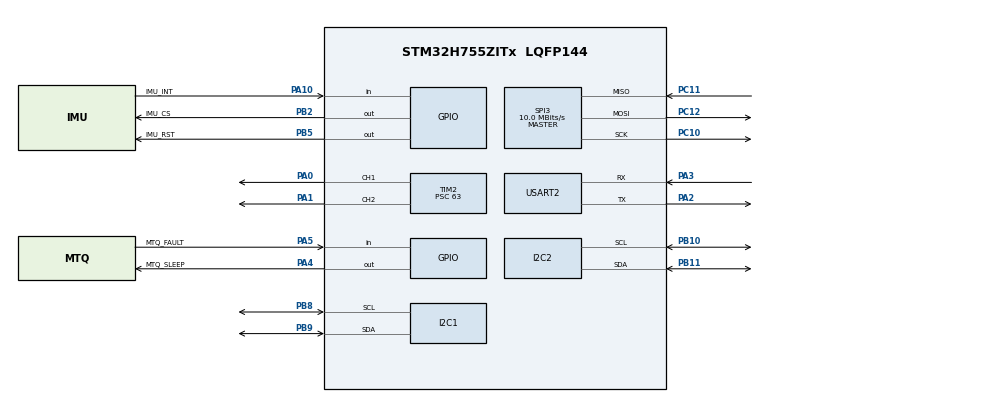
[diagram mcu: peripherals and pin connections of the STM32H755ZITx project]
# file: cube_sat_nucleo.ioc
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CORTEX_M7.default_mode_Activation=1
CortexM4.IPs=BDMA,CORTEX_M4\:I,DMA,FATFS_M4\:I,FREERTOS_M4\:I,GPIO,IWDG2\:I,MDMA,NVIC2\:I,OPENAMP_M4\:I,PDM2PCM_M4\:I,PWR,RCC,RESMGR_UTILITY,SYS_M4\:I,USB_DEVICE_M4\:I,USB_HOST_M4\:I,VREFBUF,WWDG2\:I
CortexM7.IPs=BDMA\:I,CORTEX_M7\:I,DMA\:I,FATFS_M7\:I,FREERTOS_M7\:I,GPIO\:I,IWDG1\:I,MDMA\:I,NVIC1\:I,OPENAMP_M7\:I,PDM2PCM_M7\:I,PWR\:I,RCC\:I,RESMGR_UTILITY\:I,SYS\:I,USB_DEVICE_M7\:I,USB_HOST_M7\:I,VREFBUF\:I,WWDG1\:I,MEMORYMAP\:I,TIM2\:I,TIM6\:I,SPI3\:I,I2C1\:I,USART2\:I,I2C2\:I
Dma.Request0=USART2_TX
Dma.Request1=SPI3_RX
Dma.Request2=SPI3_TX
Dma.SPI3_RX.1.Direction=DMA_PERIPH_TO_MEMORY
Dma.SPI3_RX.1.EventEnable=DISABLE
Dma.SPI3_RX.1.FIFOMode=DMA_FIFOMODE_DISABLE
Dma.SPI3_RX.1.Instance=DMA2_Stream1
Dma.SPI3_RX.1.MemDataAlignment=DMA_MDATAALIGN_BYTE
Dma.SPI3_RX.1.MemInc=DMA_MINC_ENABLE
Dma.SPI3_RX.1.Mode=DMA_NORMAL
Dma.SPI3_RX.1.PeriphDataAlignment=DMA_PDATAALIGN_BYTE
Dma.SPI3_RX.1.PeriphInc=DMA_PINC_DISABLE
Dma.SPI3_RX.1.Polarity=HAL_DMAMUX_REQ_GEN_RISING
Dma.SPI3_RX.1.Priority=DMA_PRIORITY_LOW
Dma.SPI3_RX.1.RequestNumber=1
Dma.SPI3_RX.1.SignalID=NONE
Dma.SPI3_RX.1.SyncEnable=DISABLE
Dma.SPI3_RX.1.SyncPolarity=HAL_DMAMUX_SYNC_NO_EVENT
Dma.SPI3_RX.1.SyncRequestNumber=1
Dma.SPI3_RX.1.SyncSignalID=NONE
Dma.SPI3_TX.2.Direction=DMA_MEMORY_TO_PERIPH
Dma.SPI3_TX.2.EventEnable=DISABLE
Dma.SPI3_TX.2.FIFOMode=DMA_FIFOMODE_DISABLE
Dma.SPI3_TX.2.Instance=DMA2_Stream2
Dma.SPI3_TX.2.MemDataAlignment=DMA_MDATAALIGN_BYTE
Dma.SPI3_TX.2.MemInc=DMA_MINC_ENABLE
Dma.SPI3_TX.2.Mode=DMA_NORMAL
Dma.SPI3_TX.2.PeriphDataAlignment=DMA_PDATAALIGN_BYTE
Dma.SPI3_TX.2.PeriphInc=DMA_PINC_DISABLE
Dma.SPI3_TX.2.Polarity=HAL_DMAMUX_REQ_GEN_RISING
Dma.SPI3_TX.2.Priority=DMA_PRIORITY_LOW
Dma.SPI3_TX.2.RequestNumber=1
Dma.SPI3_TX.2.SignalID=NONE
Dma.SPI3_TX.2.SyncEnable=DISABLE
Dma.SPI3_TX.2.SyncPolarity=HAL_DMAMUX_SYNC_NO_EVENT
Dma.SPI3_TX.2.SyncRequestNumber=1
Dma.SPI3_TX.2.SyncSignalID=NONE
Dma.USART2_TX.0.Direction=DMA_MEMORY_TO_PERIPH
Dma.USART2_TX.0.EventEnable=DISABLE
Dma.USART2_TX.0.FIFOMode=DMA_FIFOMODE_DISABLE
Dma.USART2_TX.0.Instance=DMA1_Stream7
Dma.USART2_TX.0.MemDataAlignment=DMA_MDATAALIGN_BYTE
Dma.USART2_TX.0.MemInc=DMA_MINC_ENABLE
Dma.USART2_TX.0.Mode=DMA_NORMAL
Dma.USART2_TX.0.PeriphDataAlignment=DMA_PDATAALIGN_BYTE
Dma.USART2_TX.0.PeriphInc=DMA_PINC_DISABLE
Dma.USART2_TX.0.Polarity=HAL_DMAMUX_REQ_GEN_RISING
Dma.USART2_TX.0.Priority=DMA_PRIORITY_LOW
Dma.USART2_TX.0.RequestNumber=1
Dma.USART2_TX.0.SignalID=NONE
Dma.USART2_TX.0.SyncEnable=DISABLE
Dma.USART2_TX.0.SyncPolarity=HAL_DMAMUX_SYNC_NO_EVENT
Dma.USART2_TX.0.SyncRequestNumber=1
Dma.USART2_TX.0.SyncSignalID=NONE
I2C1.Timing=0x00707CBB
I2C2.Timing=0x00707CBB
Mcu.Family=STM32H7
Mcu.Name=STM32H755ZITx
Mcu.Package=LQFP144
NVIC1.DMA1_Stream7_IRQn=true\:0\:0\:false\:false\:true\:false\:true\:true
NVIC1.DMA2_Stream1_IRQn=true\:0\:0\:false\:false\:true\:false\:true\:true
NVIC1.DMA2_Stream2_IRQn=true\:0\:0\:false\:false\:true\:false\:true\:true
NVIC1.PriorityGroup=NVIC_PRIORITYGROUP_4
NVIC1.SPI3_IRQn=true\:0\:0\:false\:false\:true\:true\:true\:true
NVIC1.TIM6_DAC_IRQn=true\:5\:0\:false\:false\:true\:true\:true\:true
NVIC2.PriorityGroup=NVIC_PRIORITYGROUP_4
PA0.PinAttribute=CortexM7
PA0.Signal=S_TIM2_CH1_ETR
PA1.PinAttribute=CortexM7
PA1.Signal=S_TIM2_CH2
PA10.GPIO_Label=IMU_INT
PA10.GPIO_PuPd=GPIO_PULLUP
PA10.PinAttribute=Free
PA10.Signal=GPIO_Input
PA2.GPIO_Speed=GPIO_SPEED_FREQ_VERY_HIGH
PA2.Mode=Asynchronous
PA2.PinAttribute=CortexM7
PA2.Signal=USART2_TX
PA3.GPIO_Speed=GPIO_SPEED_FREQ_VERY_HIGH
PA3.Mode=Asynchronous
PA3.PinAttribute=CortexM7
PA3.Signal=USART2_RX
PA4.GPIO_Label=MTQ_SLEEP
PA4.PinAttribute=Free
PA4.PinState=GPIO_PIN_SET
PA4.Signal=GPIO_Output
PA5.GPIO_Label=MTQ_FAULT
PA5.GPIO_PuPd=GPIO_PULLUP
PA5.PinAttribute=Free
PA5.Signal=GPIO_Input
PB10.GPIO_Speed=GPIO_SPEED_FREQ_VERY_HIGH
PB10.Mode=I2C
PB10.PinAttribute=CortexM7
PB10.Signal=I2C2_SCL
PB11.GPIO_Speed=GPIO_SPEED_FREQ_VERY_HIGH
PB11.Mode=I2C
PB11.PinAttribute=CortexM7
PB11.Signal=I2C2_SDA
PB2.GPIO_Label=IMU_CS
PB2.GPIO_PuPd=GPIO_PULLUP
PB2.GPIO_Speed=GPIO_SPEED_FREQ_HIGH
PB2.PinAttribute=Free
PB2.PinState=GPIO_PIN_SET
PB2.Signal=GPIO_Output
PB5.GPIO_Label=IMU_RST
PB5.GPIO_PuPd=GPIO_PULLUP
PB5.GPIO_Speed=GPIO_SPEED_FREQ_HIGH
PB5.PinAttribute=Free
PB5.PinState=GPIO_PIN_SET
PB5.Signal=GPIO_Output
PB8.GPIO_Speed=GPIO_SPEED_FREQ_VERY_HIGH
PB8.Mode=I2C
PB8.PinAttribute=CortexM7
PB8.Signal=I2C1_SCL
PB9.GPIO_Speed=GPIO_SPEED_FREQ_VERY_HIGH
PB9.Mode=I2C
PB9.PinAttribute=CortexM7
PB9.Signal=I2C1_SDA
PC10.GPIO_Speed=GPIO_SPEED_FREQ_VERY_HIGH
PC10.Mode=Full_Duplex_Master
PC10.PinAttribute=CortexM7
PC10.Signal=SPI3_SCK
PC11.GPIO_Speed=GPIO_SPEED_FREQ_VERY_HIGH
PC11.Mode=Full_Duplex_Master
PC11.PinAttribute=CortexM7
PC11.Signal=SPI3_MISO
PC12.GPIO_Speed=GPIO_SPEED_FREQ_VERY_HIGH
PC12.Mode=Full_Duplex_Master
PC12.PinAttribute=CortexM7
PC12.Signal=SPI3_MOSI
ProjectManager.HeapSize=M4-0x200,M7-0x200
ProjectManager.StackSize=M4-0x400,M7-0x400
ProjectManager.TargetToolchain=STM32CubeIDE
RCC.ADCFreq_Value=129000000
RCC.APB1Freq_Value=32000000
RCC.APB2Freq_Value=64000000
RCC.APB3Freq_Value=64000000
RCC.APB4Freq_Value=64000000
RCC.CortexFreq_Value=64000000
RCC.D2PPRE1=RCC_APB1_DIV2
RCC.DIVM1=4
RCC.DIVN1=10
RCC.HCLKFreq_Value=64000000
RCC.PLLFRACN=0
RCC.SYSCLKFreq_VALUE=64000000
RCC.USBFreq_Value=80000000
SH.S_TIM2_CH1_ETR.0=TIM2_CH1,PWM Generation1 CH1
SH.S_TIM2_CH2.0=TIM2_CH2,PWM Generation2 CH2
SPI3.BaudRatePrescaler=SPI_BAUDRATEPRESCALER_8
SPI3.CLKPhase=SPI_PHASE_2EDGE
SPI3.CLKPolarity=SPI_POLARITY_HIGH
SPI3.CalculateBaudRate=10.0 MBits/s
SPI3.DataSize=SPI_DATASIZE_8BIT
SPI3.Direction=SPI_DIRECTION_2LINES
SPI3.Mode=SPI_MODE_MASTER
SPI3.VirtualType=VM_MASTER
SYS.userName=SYS_M7
TIM2.Channel-PWM\ Generation1\ CH1=TIM_CHANNEL_1
TIM2.Channel-PWM\ Generation2\ CH2=TIM_CHANNEL_2
TIM2.AutoReloadPreload=TIM_AUTORELOAD_PRELOAD_ENABLE
TIM2.Period=999
TIM2.Prescaler=63
TIM6.AutoReloadPreload=TIM_AUTORELOAD_PRELOAD_ENABLE
TIM6.Period=999
TIM6.Prescaler=63
USART2.VirtualMode-Asynchronous=VM_ASYNC
VP_MEMORYMAP_VS_MEMORYMAP.Mode=CurAppReg
VP_SYS_M4_VS_Systick.Mode=SysTick
VP_TIM6_VS_ClockSourceINT.Mode=Enable_Timer
board=custom

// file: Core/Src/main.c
/* USER CODE BEGIN Header */
/**
 ******************************************************************************
 * @file           : main.c
 * @brief          : Main program body
 ******************************************************************************
 * @attention
 *
 * Copyright (c) 2025 STMicroelectronics.
 * All rights reserved.
 *
 * This software is licensed under terms that can be found in the LICENSE file
 * in the root directory of this software component.
 * If no LICENSE file comes with this software, it is provided AS-IS.
 *
 ******************************************************************************
 */
/* USER CODE END Header */
#include "main.h"
#include "dma.h"
#include "i2c.h"
#include "spi.h"
#include "tim.h"
#include "usart.h"
#include "gpio.h"

/* USER CODE BEGIN Includes */
#include "serial_log_dma.h"
#include "imu_bno085.h"
#include "inner_loop_control.h"
#include "outer_loop_control.h"
#include "config.h"
#include "teleplot.h"
#include "app_runtime.h"
#include "task.h"
#include <string.h>
/* USER CODE END Includes */

/* USER CODE BEGIN PV */
bno085_t imu;

/* USER CODE END PV */

void SystemClock_Config(void);

int main(void)
{

  /* MCU Configuration--------------------------------------------------------*/

  /* Reset of all peripherals, Initializes the Flash interface and the Systick. */
  HAL_Init();

  /* Configure the system clock */
  SystemClock_Config();

  /* Initialize all configured peripherals */
  MX_GPIO_Init();
  MX_DMA_Init();
  MX_I2C1_Init();
  MX_USART2_UART_Init();
  MX_SPI3_Init();
  MX_I2C2_Init();
  MX_TIM2_Init();
  MX_TIM6_Init();
  /* USER CODE BEGIN 2 */
  serial_log_init(&huart2);
  static uint8_t boot_banner[] = "UART DMA logger online\r\n";
  (void)HAL_UART_Transmit(&huart2, boot_banner, (uint16_t)(sizeof(boot_banner) - 1U), 20U);
  AppRuntime_Init();

  AppRuntime_Start();

  /* USER CODE END 2 */

  /* We should never get here as control is now taken by the scheduler */

  /* Infinite loop */
  /* USER CODE BEGIN WHILE */
  while (1)
  {
    // AppRuntime_RunOnce();
    /* USER CODE END WHILE */

  }
}

void SystemClock_Config(void)
{
  RCC_OscInitTypeDef RCC_OscInitStruct = {0};
  RCC_ClkInitTypeDef RCC_ClkInitStruct = {0};

  /** Configure the main internal regulator output voltage
  */
  if (HAL_PWREx_ControlVoltageScaling(PWR_REGULATOR_VOLTAGE_SCALE1) != HAL_OK)
  {
    Error_Handler();
  }

  /** Initializes the RCC Oscillators according to the specified parameters
  * in the RCC_OscInitTypeDef structure.
  */
  RCC_OscInitStruct.OscillatorType = RCC_OSCILLATORTYPE_HSI;
  RCC_OscInitStruct.HSIState = RCC_HSI_ON;
  RCC_OscInitStruct.HSICalibrationValue = RCC_HSICALIBRATION_DEFAULT;
  RCC_OscInitStruct.PLL.PLLState = RCC_PLL_NONE;
  if (HAL_RCC_OscConfig(&RCC_OscInitStruct) != HAL_OK)
  {
    Error_Handler();
  }

  /** Initializes the CPU, AHB and APB buses clocks
  */
  RCC_ClkInitStruct.ClockType = RCC_CLOCKTYPE_HCLK|RCC_CLOCKTYPE_SYSCLK
                              |RCC_CLOCKTYPE_PCLK1|RCC_CLOCKTYPE_PCLK2;
  RCC_ClkInitStruct.SYSCLKSource = RCC_SYSCLKSOURCE_HSI;
  RCC_ClkInitStruct.AHBCLKDivider = RCC_SYSCLK_DIV1;
  RCC_ClkInitStruct.APB1CLKDivider = RCC_HCLK_DIV1;
  RCC_ClkInitStruct.APB2CLKDivider = RCC_HCLK_DIV1;

  if (HAL_RCC_ClockConfig(&RCC_ClkInitStruct, FLASH_LATENCY_0) != HAL_OK)
  {
    Error_Handler();
  }
}

void HAL_TIM_PeriodElapsedCallback(TIM_HandleTypeDef *htim)
{
  /* USER CODE BEGIN Callback 0 */
  if (htim->Instance == TIM6)
  {
    AppRuntime_OnControlTickFromISR();
  }
  /* USER CODE END Callback 0 */
  if (htim->Instance == TIM7)
  {
    HAL_IncTick();
  }
}

void Error_Handler(void)
{
  __disable_irq();
  while (1)
  {
  }
}
